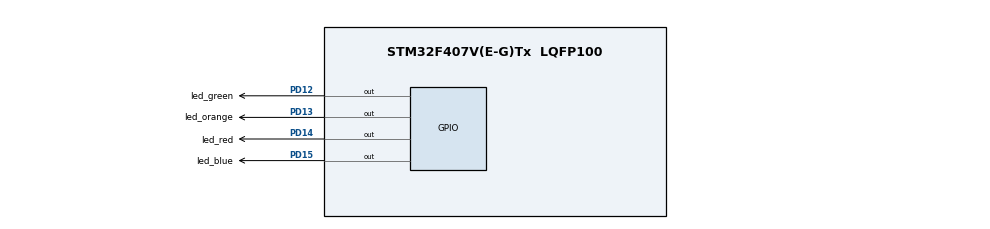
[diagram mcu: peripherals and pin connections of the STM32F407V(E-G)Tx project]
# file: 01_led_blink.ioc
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Mcu.Family=STM32F4
Mcu.Name=STM32F407V(E-G)Tx
Mcu.Package=LQFP100
NVIC.PriorityGroup=NVIC_PRIORITYGROUP_0
PA13.Mode=Serial_Wire
PA13.Signal=SYS_JTMS-SWDIO
PA14.Mode=Serial_Wire
PA14.Signal=SYS_JTCK-SWCLK
PD12.GPIO_Label=led_green
PD12.GPIO_ModeDefaultOutputPP=GPIO_MODE_OUTPUT_OD
PD12.GPIO_PuPd=GPIO_NOPULL
PD12.GPIO_Speed=GPIO_SPEED_FREQ_MEDIUM
PD12.Signal=GPIO_Output
PD13.GPIO_Label=led_orange
PD13.GPIO_ModeDefaultOutputPP=GPIO_MODE_OUTPUT_OD
PD13.GPIO_PuPd=GPIO_NOPULL
PD13.GPIO_Speed=GPIO_SPEED_FREQ_MEDIUM
PD13.Signal=GPIO_Output
PD14.GPIO_Label=led_red
PD14.GPIO_ModeDefaultOutputPP=GPIO_MODE_OUTPUT_OD
PD14.GPIO_PuPd=GPIO_NOPULL
PD14.GPIO_Speed=GPIO_SPEED_FREQ_MEDIUM
PD14.Signal=GPIO_Output
PD15.GPIO_Label=led_blue
PD15.GPIO_ModeDefaultOutputPP=GPIO_MODE_OUTPUT_OD
PD15.GPIO_PuPd=GPIO_NOPULL
PD15.GPIO_Speed=GPIO_SPEED_FREQ_MEDIUM
PD15.Signal=GPIO_Output
PH0-OSC_IN.Mode=HSE-External-Oscillator
PH0-OSC_IN.Signal=RCC_OSC_IN
PH1-OSC_OUT.Mode=HSE-External-Oscillator
PH1-OSC_OUT.Signal=RCC_OSC_OUT
ProjectManager.HeapSize=0x200
ProjectManager.StackSize=0x400
ProjectManager.TargetToolchain=STM32CubeIDE
RCC.48MHZClocksFreq_Value=48000000
RCC.AHBFreq_Value=168000000
RCC.APB1CLKDivider=RCC_HCLK_DIV4
RCC.APB1Freq_Value=42000000
RCC.APB1TimFreq_Value=84000000
RCC.APB2CLKDivider=RCC_HCLK_DIV2
RCC.APB2Freq_Value=84000000
RCC.APB2TimFreq_Value=168000000
RCC.CortexFreq_Value=168000000
RCC.HCLKFreq_Value=168000000
RCC.HSE_VALUE=8000000
RCC.HSI_VALUE=16000000
RCC.LSE_VALUE=32768
RCC.PLLM=8
RCC.PLLN=168
RCC.PLLQ=7
RCC.SYSCLKFreq_VALUE=168000000
RCC.SYSCLKSource=RCC_SYSCLKSOURCE_PLLCLK
RCC.VCOOutputFreq_Value=336000000
board=STM32F407G-DISC1

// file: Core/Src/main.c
/* USER CODE BEGIN Header */
/**
  ******************************************************************************
  * @file           : main.c
  * @brief          : Main program body
  ******************************************************************************
  * @attention
  *
  * Copyright (c) 2022 STMicroelectronics.
  * All rights reserved.
  *
  * This software is licensed under terms that can be found in the LICENSE file
  * in the root directory of this software component.
  * If no LICENSE file comes with this software, it is provided AS-IS.
  *
  ******************************************************************************
  */
/* USER CODE END Header */
#include "main.h"

uint16_t buttonState = 0;
uint16_t counter=0;

void SystemClock_Config(void);
static void MX_GPIO_Init(void);

int main(void)
{

  /* MCU Configuration--------------------------------------------------------*/

  /* Reset of all peripherals, Initializes the Flash interface and the Systick. */
  HAL_Init();

  /* Configure the system clock */
  SystemClock_Config();

  /* Initialize all configured peripherals */
  MX_GPIO_Init();

  /* Infinite loop */
  while (1){

void SystemClock_Config(void)
{
  RCC_OscInitTypeDef RCC_OscInitStruct = {0};
  RCC_ClkInitTypeDef RCC_ClkInitStruct = {0};

  /** Configure the main internal regulator output voltage
  */
  __HAL_RCC_PWR_CLK_ENABLE();
  __HAL_PWR_VOLTAGESCALING_CONFIG(PWR_REGULATOR_VOLTAGE_SCALE1);

  /** Initializes the RCC Oscillators according to the specified parameters
  * in the RCC_OscInitTypeDef structure.
  */
  RCC_OscInitStruct.OscillatorType = RCC_OSCILLATORTYPE_HSE;
  RCC_OscInitStruct.HSEState = RCC_HSE_ON;
  RCC_OscInitStruct.PLL.PLLState = RCC_PLL_ON;
  RCC_OscInitStruct.PLL.PLLSource = RCC_PLLSOURCE_HSE;
  RCC_OscInitStruct.PLL.PLLM = 4;
  RCC_OscInitStruct.PLL.PLLN = 80;
  RCC_OscInitStruct.PLL.PLLP = RCC_PLLP_DIV2;
  RCC_OscInitStruct.PLL.PLLQ = 7;
  if (HAL_RCC_OscConfig(&RCC_OscInitStruct) != HAL_OK)
  {
    Error_Handler();
  }

  /** Initializes the CPU, AHB and APB buses clocks
  */
  RCC_ClkInitStruct.ClockType = RCC_CLOCKTYPE_HCLK|RCC_CLOCKTYPE_SYSCLK
                              |RCC_CLOCKTYPE_PCLK1|RCC_CLOCKTYPE_PCLK2;
  RCC_ClkInitStruct.SYSCLKSource = RCC_SYSCLKSOURCE_PLLCLK;
  RCC_ClkInitStruct.AHBCLKDivider = RCC_SYSCLK_DIV1;
  RCC_ClkInitStruct.APB1CLKDivider = RCC_HCLK_DIV2;
  RCC_ClkInitStruct.APB2CLKDivider = RCC_HCLK_DIV2;

  if (HAL_RCC_ClockConfig(&RCC_ClkInitStruct, FLASH_LATENCY_2) != HAL_OK)
  {
    Error_Handler();
  }
}
}
static void MX_GPIO_Init(void)
{
  GPIO_InitTypeDef GPIO_InitStruct = {0};

  /* GPIO Ports Clock Enable */
  __HAL_RCC_GPIOH_CLK_ENABLE();
  __HAL_RCC_GPIOA_CLK_ENABLE();
  __HAL_RCC_GPIOD_CLK_ENABLE();

  /*Configure GPIO pin Output Level */
  HAL_GPIO_WritePin(GPIOD, led_green_Pin|led_orange_Pin|led_red_Pin|led_blue_Pin, GPIO_PIN_RESET);

  /*Configure GPIO pin : button_Pin */
  GPIO_InitStruct.Pin = button_Pin;
  GPIO_InitStruct.Mode = GPIO_MODE_INPUT;
  GPIO_InitStruct.Pull = GPIO_PULLDOWN;
  HAL_GPIO_Init(button_GPIO_Port, &GPIO_InitStruct);

  /*Configure GPIO pins : led_green_Pin led_orange_Pin led_red_Pin led_blue_Pin */
  GPIO_InitStruct.Pin = led_green_Pin|led_orange_Pin|led_red_Pin|led_blue_Pin;
  GPIO_InitStruct.Mode = GPIO_MODE_OUTPUT_PP;
  GPIO_InitStruct.Pull = GPIO_NOPULL;
  GPIO_InitStruct.Speed = GPIO_SPEED_FREQ_MEDIUM;
  HAL_GPIO_Init(GPIOD, &GPIO_InitStruct);

}

void Error_Handler(void)
{
  /* USER CODE BEGIN Error_Handler_Debug */
  /* User can add his own implementation to report the HAL error return state */
  __disable_irq();
  while (1)
  {
				buttonState = HAL_GPIO_ReadPin(button_GPIO_Port , button_Pin);

		if(buttonState){
			while(HAL_GPIO_ReadPin(button_GPIO_Port, button_Pin)){
			HAL_GPIO_WritePin(led_green_Pin |led_orange_Pin | led_red_Pin | led_blue_Pin,GPIO_PIN_SET);
				counter++;
				HAL_Delay(300);
			elseif{

				HAL_GPIO_WritePin(led_green_Pin | led_orange_Pin | led_red_Pin | led_blue_Pin);
  }
	elseif(counter%4==1){
			HAL_GPIO_WritePin(GPIOD, led_green_Pin, GPIO_PIN_SET);
			HAL_GPIO_WritePin(GPIOD, led_orange_Pin | led_red_Pin |led_blue_Pin, GPIO_PIN_RESET);
}
	elseif(counter%4==2){
		HAL_GPIO_WritePin(GPIOD, led_orange_Pin,GPIO_PIN_RESET);
		HAL_GPIO_WritePin(GPIOD, led_green_Pin | led_red_Pin |led_blue_Pin, GPIO_PIN_RESET);
	}
	elseif(counter%4==3){
		HAL_GPIO_WritePin(GPIOD,led_red_Pin, GPIO_PIN_SET);
		HAL_GPIO_WritePin(GPIOD, led_green_Pin | led_orange_Pin|led_blue_Pin, GPIO_PIN_RESET);
	}
  elseif(counter4==0){
	HAL_GPIO_WritePin(GPIOD,led_blue_Pin, GPIO_PIN_SET);
	HAL_GPIO_WritePin(GPIOD, led_green_Pin | led_orange_Pin | led_red_Pin, GPIO_PIN_RESET);
	}
	else{
	HAL_GPIO_WritePin(GPIOD, led_green_Pin | led_orange_Pin | led_red_Pin |led_blue_Pin, GPIO_PIN_RESET);
	}
}
}
}
}
}
